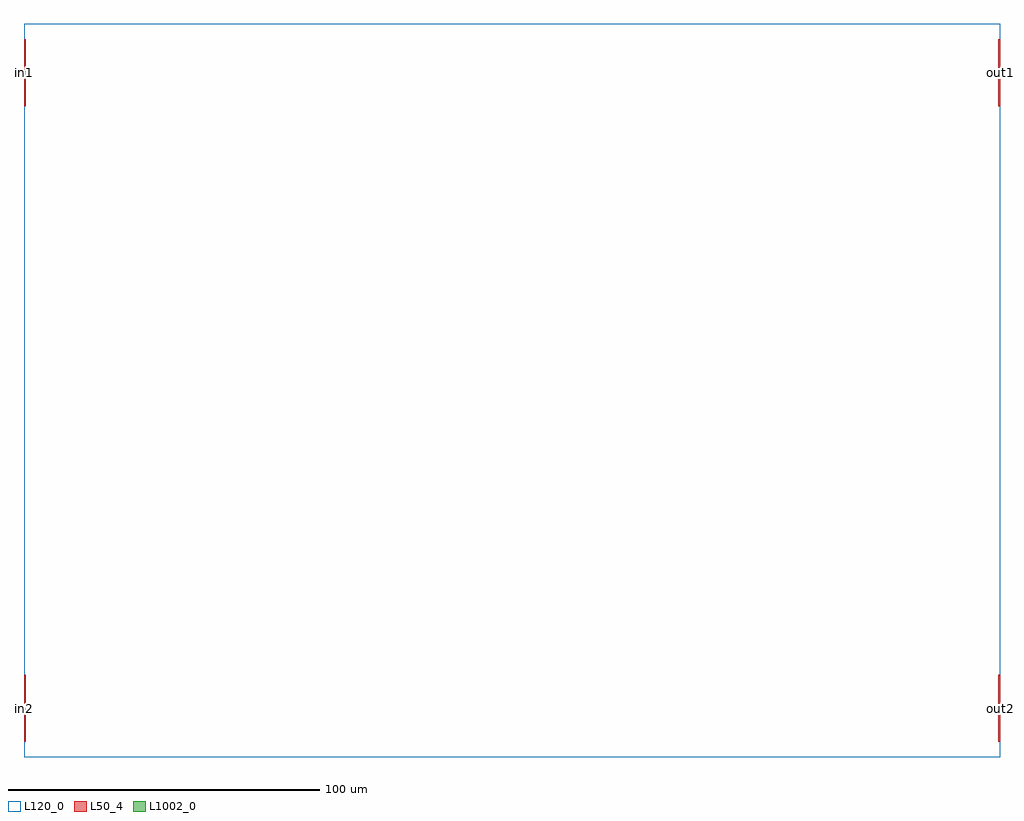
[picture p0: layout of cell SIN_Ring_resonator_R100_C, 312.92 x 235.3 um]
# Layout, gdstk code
import gdstk
lib = gdstk.Library(unit=1e-6, precision=1e-09)
def R(c, l, rs):  # rectangles x0, y0, x1, y1
    for r in rs: c.add(gdstk.rectangle(r[:2], r[2:], *l))
L50_4 = (50, 4)
L120_0 = (120, 0)
L1002_0 = (1002, 0)

sin_ring_resonator_r100_ = lib.new_cell('SIN_Ring_resonator_R100_C')
R(sin_ring_resonator_r100_, L50_4, [(0,5,0.5,15), (312.42,5,312.92,15), (0,16.5,0.5,26.5), (312.42,16.5,312.92,26.5), (0,208.8,0.5,218.8), (312.42,208.8,312.92,218.8), (0,220.3,0.5,230.3), (312.42,220.3,312.92,230.3)])
R(sin_ring_resonator_r100_, L120_0, [(0,0,312.92,235.3)])
R(sin_ring_resonator_r100_, L1002_0, [(0,15,0.5,16.5), (312.42,15,312.92,16.5), (0,218.8,0.5,220.3), (312.42,218.8,312.92,220.3)])
sin_ring_resonator_r100_.add(gdstk.Label('out2', (312.92,15.735), layer=1000, texttype=0))
sin_ring_resonator_r100_.add(gdstk.Label('out1', (312.92,219.557), layer=1000, texttype=0))
sin_ring_resonator_r100_.add(gdstk.Label('in1', (0,219.505), layer=1000, texttype=0))
sin_ring_resonator_r100_.add(gdstk.Label('in2', (0,15.74), layer=1000, texttype=0))

lib.write_gds('SIN_Ring_resonator_R100_C.gds')
